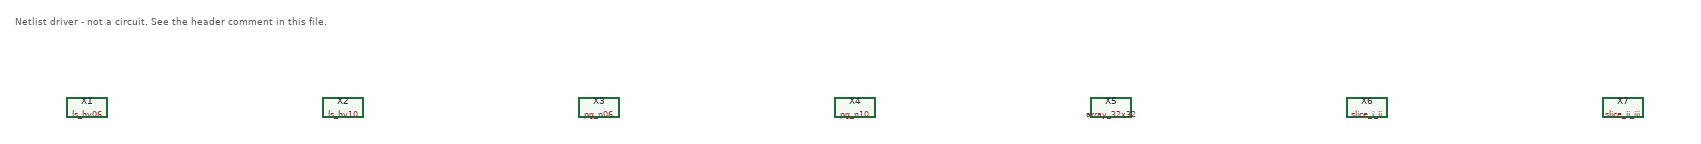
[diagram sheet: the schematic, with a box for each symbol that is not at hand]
v {xschem version=3.4.7 file_version=1.2

* gf180-antifuse: netlist driver for the array and addressing-stage library.
* GENERATED by design/gen_array.py. Not a circuit.
*
* Same reason as cells/cell_library.sch: xschem emits parameterized .subckt
* lines (the level shifter and pass-gate sizing parameters) only for
* sub-schematics, and split_files then writes one netlist per symbol.
* Netlisting this driver therefore produces ls_hv06.spice, ls_hv10.spice,
* pg_n06.spice, pg_n10.spice, array_32x32.spice and one file per slice.
* Its own top-level netlist is discarded.
}
G {}
K {}
V {}
S {}
E {}
C {ls_hv06.sym} 300 300 0 0 {name=X1}
C {ls_hv10.sym} 800 300 0 0 {name=X2}
C {pg_n06.sym} 1300 300 0 0 {name=X3}
C {pg_n10.sym} 1800 300 0 0 {name=X4}
C {array_32x32.sym} 2300 300 0 0 {name=X5}
C {slice_i_ii.sym} 2800 300 0 0 {name=X6}
C {slice_ii_iii.sym} 3300 300 0 0 {name=X7}
T {Netlist driver - not a circuit. See the header comment in this file.} 160 120 0 0 0.5 0.5 {}
